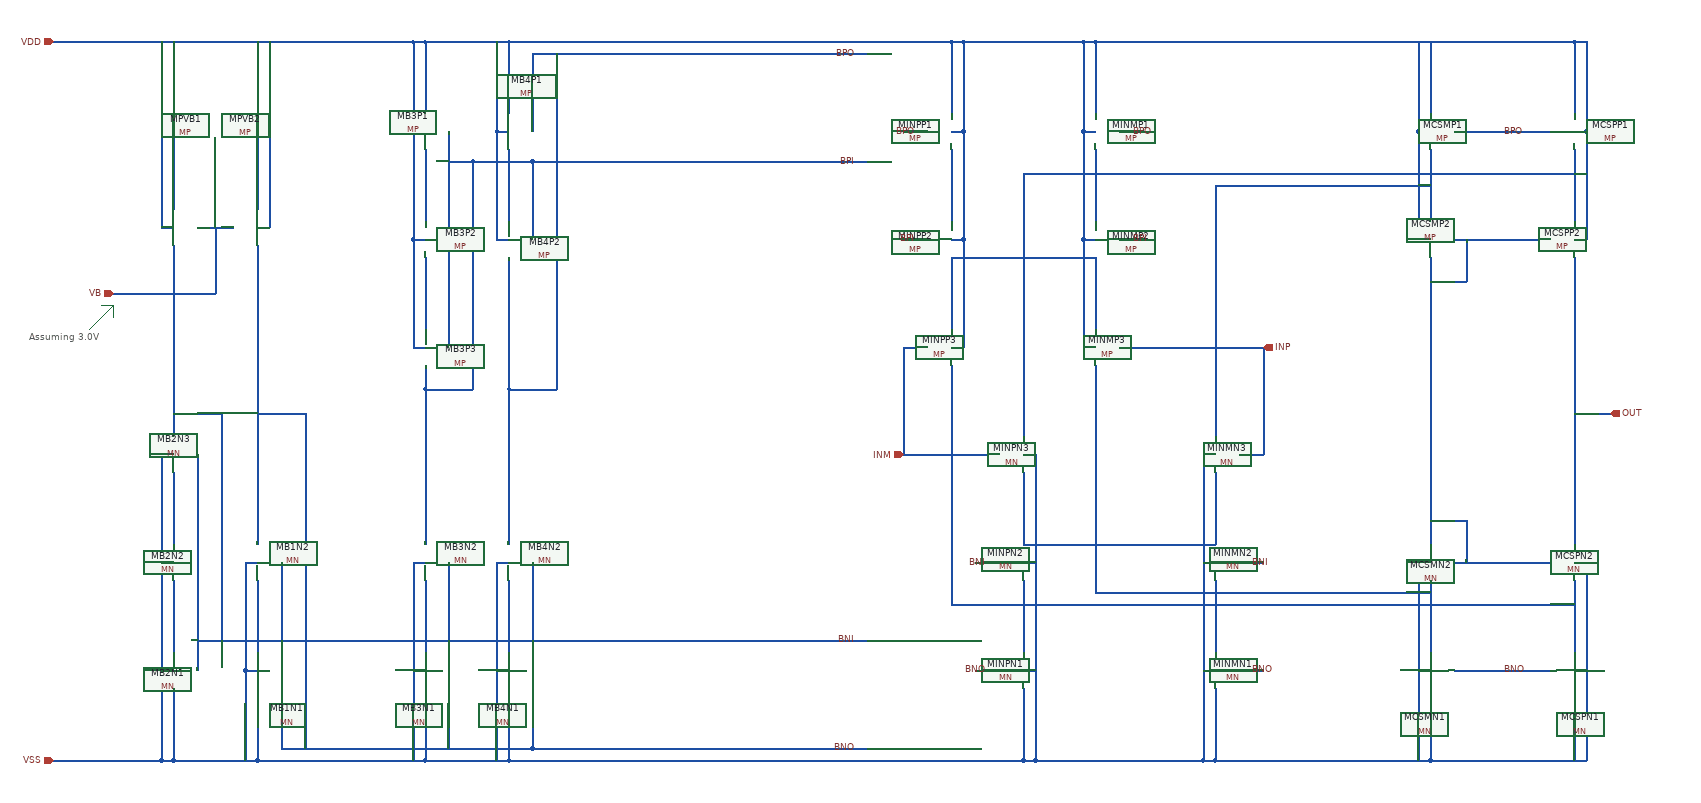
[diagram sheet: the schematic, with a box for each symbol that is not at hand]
v {xschem version=3.4.8RC file_version=1.3}
G {}
K {}
V {}
S {}
F {}
E {}
L 4 -540 -760 -520 -760 {}
L 4 -520 -760 -520 -740 {}
L 4 -560 -720 -520 -760 {}
P 4 1 -740 -1280 {}
T {Assuming 3.0V} -660 -720 0 0 0.4 0.4 {}
N 140 -1020 140 -900 {lab=#net1}
N 120 -870 140 -870 {lab=VDD}
N 120 -1050 120 -870 {lab=VDD}
N 120 -1050 140 -1050 {lab=VDD}
N 120 -1050 140 -1050 {lab=VDD}
N 120 -1080 120 -1050 {lab=VDD}
N 0 -1020 0 -900 {lab=#net2}
N -20 -870 0 -870 {lab=VDD}
N -20 -1050 -20 -870 {lab=VDD}
N -20 -1050 0 -1050 {lab=VDD}
N -20 -1050 0 -1050 {lab=VDD}
N -20 -1080 -20 -1050 {lab=VDD}
N 0 -840 0 -720 {lab=#net3}
N -20 -690 0 -690 {lab=VDD}
N -20 -870 -20 -690 {lab=VDD}
N 40 -870 40 -690 {lab=BPI}
N 40 -1050 40 -870 {lab=BPI}
N 80 -1000 80 -620 {lab=BPI}
N 0 -620 80 -620 {lab=BPI}
N 0 -660 0 -620 {lab=BPI}
N 0 -1200 0 -1080 {lab=VDD}
N -20 -1200 -20 -1080 {lab=VDD}
N -20 -1200 0 -1200 {lab=VDD}
N 0 -1200 140 -1200 {lab=VDD}
N 140 -1200 140 -1080 {lab=VDD}
N 120 -1200 120 -1080 {lab=VDD}
N -140 -1200 -20 -1200 {lab=VDD}
N -160 -1200 -140 -1200 {lab=VDD}
N 180 -1000 300 -1000 {lab=BPI}
N 80 -1000 180 -1000 {lab=BPI}
N 40 -1000 80 -1000 {lab=BPI}
N 180 -1000 180 -870 {lab=BPI}
N 180 -1180 180 -1050 {lab=BPO}
N 180 -1180 300 -1180 {lab=BPO}
N 140 -1200 300 -1200 {lab=VDD}
N 880 -1020 880 -900 {lab=#net4}
N 880 -870 900 -870 {lab=VDD}
N 900 -1050 900 -870 {lab=VDD}
N 880 -1050 900 -1050 {lab=VDD}
N 880 -1050 900 -1050 {lab=VDD}
N 900 -1080 900 -1050 {lab=VDD}
N 880 -840 880 -720 {lab=#net5}
N 880 -690 900 -690 {lab=VDD}
N 900 -870 900 -690 {lab=VDD}
N 880 -1200 880 -1080 {lab=VDD}
N 900 -1200 900 -1080 {lab=VDD}
N 880 -1200 900 -1200 {lab=VDD}
N 800 -1050 840 -1050 {lab=BPO}
N 800 -870 840 -870 {lab=BPI}
N 800 -690 840 -690 {lab=INM}
N 1120 -1020 1120 -900 {lab=#net6}
N 1100 -870 1120 -870 {lab=VDD}
N 1100 -1050 1100 -870 {lab=VDD}
N 1100 -1050 1120 -1050 {lab=VDD}
N 1100 -1050 1120 -1050 {lab=VDD}
N 1100 -1080 1100 -1050 {lab=VDD}
N 1120 -840 1120 -720 {lab=#net5}
N 1100 -690 1120 -690 {lab=VDD}
N 1100 -870 1100 -690 {lab=VDD}
N 1120 -1200 1120 -1080 {lab=VDD}
N 1100 -1200 1100 -1080 {lab=VDD}
N 1100 -1200 1120 -1200 {lab=VDD}
N 1160 -1050 1200 -1050 {lab=BPO}
N 1160 -870 1200 -870 {lab=BPI}
N 920 -1200 1100 -1200 {lab=VDD}
N 220 -1180 220 -620 {lab=BPO}
N 140 -620 220 -620 {lab=BPO}
N 140 -840 140 -620 {lab=BPO}
N 140 -620 140 -540 {lab=BPO}
N 880 -660 880 -540 {lab=#net7}
N 1120 -660 1120 -540 {lab=#net8}
N 140 -480 140 -360 {lab=BPO}
N 140 -540 140 -480 {lab=BPO}
N 0 -620 0 -540 {lab=BPI}
N 0 -480 0 -360 {lab=BPI}
N 0 -540 0 -480 {lab=BPI}
N 120 -330 140 -330 {lab=VSS}
N 140 -300 140 -180 {lab=#net9}
N 0 -300 0 -180 {lab=#net10}
N 140 -120 140 0 {lab=VSS}
N 0 -120 0 0 {lab=VSS}
N 0 0 140 0 {lab=VSS}
N -280 -620 -280 -540 {lab=BNO}
N -280 -480 -280 -360 {lab=BNO}
N -280 -540 -280 -480 {lab=BNO}
N -420 -620 -420 -540 {lab=BNI}
N -420 -480 -420 -360 {lab=#net11}
N -300 -330 -280 -330 {lab=VSS}
N -280 -300 -280 -180 {lab=#net12}
N -420 -300 -420 -180 {lab=#net13}
N -280 -120 -280 0 {lab=VSS}
N -420 -120 -420 0 {lab=VSS}
N -420 0 -280 0 {lab=VSS}
N -140 0 0 0 {lab=VSS}
N -280 0 -140 0 {lab=VSS}
N -300 -150 -280 -150 {lab=VSS}
N -300 -150 -300 -10 {lab=VSS}
N -300 -10 -300 0 {lab=VSS}
N -300 -330 -300 -150 {lab=VSS}
N -240 -20 180 -20 {lab=BNO}
N 180 -150 180 -20 {lab=BNO}
N 40 -150 40 -20 {lab=BNO}
N -240 -150 -240 -20 {lab=BNO}
N 180 -20 300 -20 {lab=BNO}
N -200 -400 -200 -20 {lab=BNO}
N -440 -510 -420 -510 {lab=VSS}
N -440 -510 -440 0 {lab=VSS}
N -440 0 -420 0 {lab=VSS}
N -440 -150 -420 -150 {lab=VSS}
N -440 -330 -420 -330 {lab=VSS}
N -380 -510 -380 -330 {lab=BNI}
N -380 -330 -380 -150 {lab=BNI}
N -380 -200 300 -200 {lab=BNI}
N -240 -330 -240 -200 {lab=BNI}
N -340 -580 -340 -200 {lab=BNI}
N -420 -580 -340 -580 {lab=BNI}
N -280 -580 -200 -580 {lab=BNO}
N -200 -580 -200 -400 {lab=BNO}
N 1000 -620 1000 -540 {lab=#net14}
N 1000 -480 1000 -360 {lab=#net15}
N 1000 -300 1000 -180 {lab=#net16}
N 1000 -120 1000 0 {lab=VSS}
N 860 0 1000 0 {lab=VSS}
N 1000 -510 1020 -510 {lab=VSS}
N 1020 -510 1020 0 {lab=VSS}
N 1000 0 1020 0 {lab=VSS}
N 1000 -150 1020 -150 {lab=VSS}
N 1000 -330 1020 -330 {lab=VSS}
N 900 -1200 920 -1200 {lab=VDD}
N 880 -840 1120 -840 {lab=#net5}
N 800 -510 960 -510 {lab=INM}
N 800 -690 800 -510 {lab=INM}
N 920 -330 960 -330 {lab=BNI}
N 920 -150 960 -150 {lab=BNO}
N 140 0 280 0 {lab=VSS}
N 320 -1000 740 -1000 {lab=BPI}
N 320 -1180 740 -1180 {lab=BPO}
N 40 -330 40 -200 {lab=BNI}
N 180 -330 180 -200 {lab=BNI}
N 120 -330 120 -0 {lab=VSS}
N -20 -330 -20 0 {lab=VSS}
N -20 -330 -0 -330 {lab=VSS}
N -20 -150 -0 -150 {lab=VSS}
N 120 -150 140 -150 {lab=VSS}
N 300 -20 740 -20 {lab=BNO}
N 300 -200 740 -200 {lab=BNI}
N 420 -0 740 -0 {lab=VSS}
N 480 -1200 740 -1200 {lab=VDD}
N -520 0 -440 -0 {lab=VSS}
N -580 -0 -520 -0 {lab=VSS}
N 1320 -620 1320 -540 {lab=#net17}
N 1320 -480 1320 -360 {lab=#net15}
N 1320 -300 1320 -180 {lab=#net18}
N 1320 -120 1320 0 {lab=VSS}
N 1300 -510 1320 -510 {lab=VSS}
N 1300 -510 1300 0 {lab=VSS}
N 1300 0 1320 0 {lab=VSS}
N 1300 -150 1320 -150 {lab=VSS}
N 1300 -330 1320 -330 {lab=VSS}
N 1360 -330 1400 -330 {lab=BNI}
N 1360 -150 1400 -150 {lab=BNO}
N 1360 -510 1400 -510 {lab=INM}
N 1400 -690 1400 -510 {lab=INM}
N 1020 0 1300 0 {lab=VSS}
N 800 -1200 880 -1200 {lab=VDD}
N 1120 -1200 1480 -1200 {lab=VDD}
N 1320 0 1520 -0 {lab=VSS}
N 1680 -1020 1680 -900 {lab=#net17}
N 1660 -870 1680 -870 {lab=VDD}
N 1660 -1050 1660 -870 {lab=VDD}
N 1660 -1050 1680 -1050 {lab=VDD}
N 1660 -1050 1680 -1050 {lab=VDD}
N 1660 -1080 1660 -1050 {lab=VDD}
N 1680 -840 1680 -720 {lab=#net19}
N 1680 -1200 1680 -1080 {lab=VDD}
N 1660 -1200 1660 -1080 {lab=VDD}
N 1660 -1200 1680 -1200 {lab=VDD}
N 1720 -1050 1760 -1050 {lab=BPO}
N 1720 -870 1760 -870 {lab=#net19}
N 1920 -1020 1920 -900 {lab=#net14}
N 1920 -870 1940 -870 {lab=VDD}
N 1940 -1050 1940 -870 {lab=VDD}
N 1920 -1050 1940 -1050 {lab=VDD}
N 1920 -1050 1940 -1050 {lab=VDD}
N 1940 -1080 1940 -1050 {lab=VDD}
N 1920 -840 1920 -720 {lab=OUT}
N 1920 -1200 1920 -1080 {lab=VDD}
N 1940 -1200 1940 -1080 {lab=VDD}
N 1920 -1200 1940 -1200 {lab=VDD}
N 1840 -1050 1880 -1050 {lab=BPO}
N 1840 -870 1880 -870 {lab=#net19}
N 1560 -1200 1920 -1200 {lab=VDD}
N 1760 -1050 1840 -1050 {lab=BPO}
N 1760 -870 1840 -870 {lab=#net19}
N 1680 -300 1680 -180 {lab=#net8}
N 1660 -150 1680 -150 {lab=VSS}
N 1660 -330 1680 -330 {lab=VSS}
N 1680 -120 1680 0 {lab=VSS}
N 1520 0 1680 -0 {lab=VSS}
N 1720 -150 1740 -150 {lab=BNO}
N 1920 -300 1920 -180 {lab=#net7}
N 1920 -120 1920 0 {lab=VSS}
N 1920 -150 1940 -150 {lab=VSS}
N 1920 -330 1940 -330 {lab=VSS}
N 1740 -150 1880 -150 {lab=BNO}
N 1720 -330 1880 -330 {lab=#net19}
N 1120 -280 1680 -280 {lab=#net8}
N 1120 -540 1120 -280 {lab=#net8}
N 880 -540 880 -260 {lab=#net7}
N 880 -260 1920 -260 {lab=#net7}
N 1680 0 1940 0 {lab=VSS}
N 1010 -980 1920 -980 {lab=#net14}
N 1320 -960 1680 -960 {lab=#net17}
N 1160 -690 1400 -690 {lab=INM}
N 1320 -960 1320 -620 {lab=#net17}
N 1000 -980 1010 -980 {lab=#net14}
N 1000 -980 1000 -620 {lab=#net14}
N 740 0 860 0 {lab=VSS}
N 740 -1200 800 -1200 {lab=VDD}
N -620 -1200 -160 -1200 {lab=VDD}
N -620 -0 -580 -0 {lab=VSS}
N 1920 -580 1980 -580 {lab=OUT}
N -420 -860 -420 -620 {lab=BNI}
N -420 -1200 -420 -920 {lab=VDD}
N -280 -1200 -280 -920 {lab=VDD}
N -280 -890 -260 -890 {lab=VDD}
N -260 -1200 -260 -890 {lab=VDD}
N -440 -890 -420 -890 {lab=VDD}
N -440 -1200 -440 -890 {lab=VDD}
N -380 -890 -320 -890 {lab=VB}
N -350 -890 -350 -780 {lab=VB}
N -520 -780 -350 -780 {lab=VB}
N -280 -860 -280 -620 {lab=BNO}
N 1480 -1200 1560 -1200 {lab=VDD}
N 1920 -660 1920 -360 {lab=OUT}
N 1680 -660 1680 -360 {lab=#net19}
N 1000 -360 1320 -360 {lab=#net15}
N 1660 -330 1660 -0 {lab=VSS}
N 1940 -330 1940 -0 {lab=VSS}
N 1680 -720 1680 -660 {lab=#net19}
N 1920 -720 1920 -660 {lab=OUT}
N 300 -1200 480 -1200 {lab=VDD}
N 300 -1180 320 -1180 {lab=BPO}
N 300 -1000 320 -1000 {lab=BPI}
N 280 0 420 -0 {lab=VSS}
N 1680 -800 1740 -800 {lab=#net19}
N 1680 -400 1740 -400 {lab=#net19}
N 1740 -400 1740 -330 {lab=#net19}
N 1740 -870 1740 -800 {lab=#net19}
C {MP.sym} 180 -1050 0 1 {name=MB4P1 model=PMOS w=12u l=8u m=4 as=0 ad=0 ps=0 pd=0 nrd=0 nrs=0 spiceprefix=X}
C {MP.sym} 180 -870 0 1 {name=MB4P2 model=PMOS w=12u l=8u m=4 as=0 ad=0 ps=0 pd=0 nrd=0 nrs=0 spiceprefix=X}
C {MP.sym} 40 -1050 0 1 {name=MB3P1 model=PMOS w=12u l=8u m=2 as=0 ad=0 ps=0 pd=0 nrd=0 nrs=0 spiceprefix=X}
C {MP.sym} 40 -870 0 1 {name=MB3P2 model=PMOS w=12u l=8u m=2 as=0 ad=0 ps=0 pd=0 nrd=0 nrs=0 spiceprefix=X}
C {MP.sym} 40 -690 0 1 {name=MB3P3 model=PMOS w=12u l=8u m=2 as=0 ad=0 ps=0 pd=0 nrd=0 nrs=0 spiceprefix=X}
C {devices/lab_wire.sym} 720 -1180 0 0 {name=p3 sig_type=std_logic lab=BPO}
C {devices/lab_wire.sym} 720 -1000 0 0 {name=p1 sig_type=std_logic lab=BPI}
C {MP.sym} 840 -1050 0 0 {name=MINPP1 model=PMOS w=12u l=8u m=8 as=0 ad=0 ps=0 pd=0 nrd=0 nrs=0 spiceprefix=X}
C {MP.sym} 840 -870 0 0 {name=MINPP2 model=PMOS w=12u l=8u m=8 as=0 ad=0 ps=0 pd=0 nrd=0 nrs=0 spiceprefix=X}
C {MP.sym} 840 -690 0 0 {name=MINPP3 model=PMOS w=12u l=8u m=4 as=0 ad=0 ps=0 pd=0 nrd=0 nrs=0 spiceprefix=X}
C {devices/lab_wire.sym} 820 -1050 0 0 {name=p2 sig_type=std_logic lab=BPO}
C {devices/lab_wire.sym} 820 -870 0 0 {name=p4 sig_type=std_logic lab=BPI}
C {MP.sym} 1160 -1050 0 1 {name=MINMP1 model=PMOS w=12u l=8u m=8 as=0 ad=0 ps=0 pd=0 nrd=0 nrs=0 spiceprefix=X}
C {MP.sym} 1160 -870 0 1 {name=MINMP2 model=PMOS w=12u l=8u m=8 as=0 ad=0 ps=0 pd=0 nrd=0 nrs=0 spiceprefix=X}
C {MP.sym} 1160 -690 0 1 {name=MINMP3 model=PMOS w=12u l=8u m=4 as=0 ad=0 ps=0 pd=0 nrd=0 nrs=0 spiceprefix=X}
C {devices/lab_wire.sym} 1180 -1050 0 1 {name=p5 sig_type=std_logic lab=BPO}
C {devices/lab_wire.sym} 1180 -870 0 1 {name=p6 sig_type=std_logic lab=BPI}
C {MN.sym} 180 -330 0 1 {name=MB4N2 model=NMOS w=12u l=8u m=2 as=0 ad=0 ps=0 pd=0 nrd=0 nrs=0 spiceprefix=X}
C {MN.sym} 40 -330 0 1 {name=MB3N2 model=NMOS w=12u l=8u m=2 as=0 ad=0 ps=0 pd=0 nrd=0 nrs=0 spiceprefix=X}
C {MN.sym} 180 -150 0 1 {name=MB4N1 model=NMOS w=12u l=8u m=2 as=0 ad=0 ps=0 pd=0 nrd=0 nrs=0 spiceprefix=X}
C {MN.sym} 40 -150 0 1 {name=MB3N1 model=NMOS w=12u l=8u m=2 as=0 ad=0 ps=0 pd=0 nrd=0 nrs=0 spiceprefix=X}
C {MN.sym} -240 -330 0 1 {name=MB1N2 model=NMOS w=12u l=8u m=2 as=0 ad=0 ps=0 pd=0 nrd=0 nrs=0 spiceprefix=X}
C {MN.sym} -380 -330 0 1 {name=MB2N2 model=NMOS w=12u l=8u m=1 as=0 ad=0 ps=0 pd=0 nrd=0 nrs=0 spiceprefix=X}
C {MN.sym} -240 -150 0 1 {name=MB1N1 model=NMOS w=12u l=8u m=2 as=0 ad=0 ps=0 pd=0 nrd=0 nrs=0 spiceprefix=X}
C {MN.sym} -380 -150 0 1 {name=MB2N1 model=NMOS w=12u l=8u m=1 as=0 ad=0 ps=0 pd=0 nrd=0 nrs=0 spiceprefix=X}
C {MN.sym} -380 -510 0 1 {name=MB2N3 model=NMOS w=12u l=8u m=1 as=0 ad=0 ps=0 pd=0 nrd=0 nrs=0 spiceprefix=X}
C {devices/lab_wire.sym} 720 -200 0 0 {name=p8 sig_type=std_logic lab=BNI}
C {devices/lab_wire.sym} 720 -20 0 0 {name=p9 sig_type=std_logic lab=BNO}
C {MN.sym} 960 -330 0 0 {name=MINPN2 model=NMOS w=12u l=8u m=4 as=0 ad=0 ps=0 pd=0 nrd=0 nrs=0 spiceprefix=X}
C {MN.sym} 960 -150 0 0 {name=MINPN1 model=NMOS w=12u l=8u m=4 as=0 ad=0 ps=0 pd=0 nrd=0 nrs=0 spiceprefix=X}
C {MN.sym} 960 -510 0 0 {name=MINPN3 model=NMOS w=12u l=8u m=2 as=0 ad=0 ps=0 pd=0 nrd=0 nrs=0 spiceprefix=X}
C {devices/lab_wire.sym} 940 -330 0 0 {name=p13 sig_type=std_logic lab=BNI}
C {devices/lab_wire.sym} 940 -150 0 0 {name=p14 sig_type=std_logic lab=BNO}
C {MN.sym} 1360 -330 0 1 {name=MINMN2 model=NMOS w=12u l=8u m=4 as=0 ad=0 ps=0 pd=0 nrd=0 nrs=0 spiceprefix=X}
C {MN.sym} 1360 -150 0 1 {name=MINMN1 model=NMOS w=12u l=8u m=4 as=0 ad=0 ps=0 pd=0 nrd=0 nrs=0 spiceprefix=X}
C {MN.sym} 1360 -510 0 1 {name=MINMN3 model=NMOS w=12u l=8u m=2 as=0 ad=0 ps=0 pd=0 nrd=0 nrs=0 spiceprefix=X}
C {devices/lab_wire.sym} 1380 -330 0 1 {name=p16 sig_type=std_logic lab=BNI}
C {devices/lab_wire.sym} 1380 -150 0 1 {name=p17 sig_type=std_logic lab=BNO}
C {MP.sym} 1720 -1050 0 1 {name=MCSMP1 model=PMOS w=12u l=8u m=16 as=0 ad=0 ps=0 pd=0 nrd=0 nrs=0 spiceprefix=X}
C {MP.sym} 1720 -870 0 1 {name=MCSMP2 model=PMOS w=12u l=8u m=8 as=0 ad=0 ps=0 pd=0 nrd=0 nrs=0 spiceprefix=X}
C {MP.sym} 1880 -1050 0 0 {name=MCSPP1 model=PMOS w=12u l=8u m=16 as=0 ad=0 ps=0 pd=0 nrd=0 nrs=0 spiceprefix=X}
C {MP.sym} 1880 -870 0 0 {name=MCSPP2 model=PMOS w=12u l=8u m=8 as=0 ad=0 ps=0 pd=0 nrd=0 nrs=0 spiceprefix=X}
C {MN.sym} 1720 -330 0 1 {name=MCSMN2 model=NMOS w=12u l=8u m=4 as=0 ad=0 ps=0 pd=0 nrd=0 nrs=0 spiceprefix=X}
C {MN.sym} 1720 -150 0 1 {name=MCSMN1 model=NMOS w=12u l=8u m=8 as=0 ad=0 ps=0 pd=0 nrd=0 nrs=0 spiceprefix=X}
C {MN.sym} 1880 -330 0 0 {name=MCSPN2 model=NMOS w=12u l=8u m=4 as=0 ad=0 ps=0 pd=0 nrd=0 nrs=0 spiceprefix=X}
C {MN.sym} 1880 -150 0 0 {name=MCSPN1 model=NMOS w=12u l=8u m=8 as=0 ad=0 ps=0 pd=0 nrd=0 nrs=0 spiceprefix=X}
C {devices/iopin.sym} -620 -1200 2 0 {name=p22 lab=VDD}
C {devices/iopin.sym} -620 0 2 0 {name=p23 lab=VSS}
C {devices/ipin.sym} 800 -510 0 0 {name=p7 lab=INM}
C {devices/ipin.sym} 1400 -690 0 1 {name=p24 lab=INP}
C {devices/opin.sym} 1980 -580 0 0 {name=p25 lab=OUT}
C {MP.sym} -380 -890 0 1 {name=MPVB1 model=PMOS w=12u l=8u m=2 as=0 ad=0 ps=0 pd=0 nrd=0 nrs=0 spiceprefix=X}
C {MP.sym} -320 -890 0 0 {name=MPVB2 model=PMOS w=12u l=8u m=2 as=0 ad=0 ps=0 pd=0 nrd=0 nrs=0 spiceprefix=X}
C {devices/ipin.sym} -520 -780 0 0 {name=p11 lab=VB}
C {devices/lab_wire.sym} 1800 -150 0 1 {name=p10 sig_type=std_logic lab=BNO}
C {devices/lab_wire.sym} 1800 -1050 0 1 {name=p12 sig_type=std_logic lab=BPO}
